One B-rep face of a CAD part: STEP entity #853.
In plain terms, the planar face has unit normal (0, 0, -1).
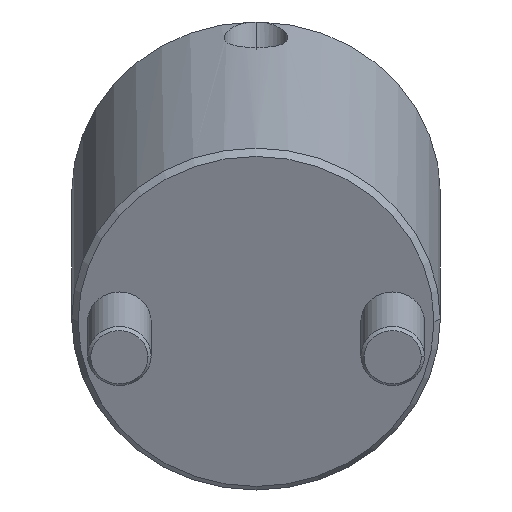
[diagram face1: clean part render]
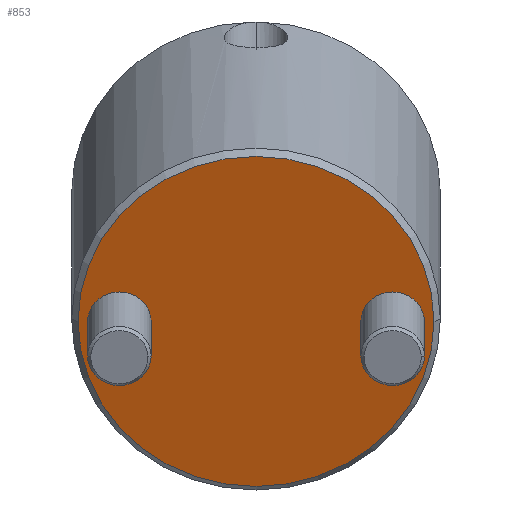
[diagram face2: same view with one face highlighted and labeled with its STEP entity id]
Its self-contained STEP definition (entity closure, numbers rounded to 3 decimals):
#432=CARTESIAN_POINT('',(0.,0.,
0.));
#433=DIRECTION('',(0.,0.,-1.));
#434=DIRECTION('',(0.,-1.,0.));
#435=AXIS2_PLACEMENT_3D('',#432,#433,#434);
#437=CARTESIAN_POINT('',(0.,0.,
0.));
#438=DIRECTION('',(0.,0.,-1.));
#439=DIRECTION('',(0.,1.,0.));
#440=AXIS2_PLACEMENT_3D('',#437,#438,#439);
#442=CARTESIAN_POINT('',(0.,-21.5,0.));
#443=DIRECTION('',(0.,0.,-1.));
#444=DIRECTION('',(0.,-1.,0.));
#445=AXIS2_PLACEMENT_3D('',#442,#443,#444);
#447=CARTESIAN_POINT('',(0.,-21.5,0.));
#448=DIRECTION('',(0.,0.,-1.));
#449=DIRECTION('',(0.,1.,0.));
#450=AXIS2_PLACEMENT_3D('',#447,#448,#449);
#452=CARTESIAN_POINT('',(0.,21.5,0.));
#453=DIRECTION('',(0.,0.,-1.));
#454=DIRECTION('',(0.,-1.,0.));
#455=AXIS2_PLACEMENT_3D('',#452,#453,#454);
#457=CARTESIAN_POINT('',(0.,21.5,0.));
#458=DIRECTION('',(0.,0.,-1.));
#459=DIRECTION('',(0.,1.,0.));
#460=AXIS2_PLACEMENT_3D('',#457,#458,#459);
#777=CARTESIAN_POINT('',(0.,-28.,0.));
#778=CARTESIAN_POINT('',(0.,28.,0.));
#779=VERTEX_POINT('',#777);
#780=VERTEX_POINT('',#778);
#806=CARTESIAN_POINT('',(0.,-26.5,0.));
#807=CARTESIAN_POINT('',(0.,-16.5,0.));
#808=VERTEX_POINT('',#806);
#809=VERTEX_POINT('',#807);
#810=CARTESIAN_POINT('',(0.,16.5,0.));
#811=CARTESIAN_POINT('',(0.,26.5,0.));
#812=VERTEX_POINT('',#810);
#813=VERTEX_POINT('',#811);
#830=CARTESIAN_POINT('',(0.,0.,0.));
#831=DIRECTION('',(0.,0.,1.));
#832=DIRECTION('',(0.,1.,0.));
#833=AXIS2_PLACEMENT_3D('',#830,#831,#832);
#834=PLANE('',#833);
#836=ORIENTED_EDGE('',*,*,#835,.F.);
#838=ORIENTED_EDGE('',*,*,#837,.F.);
#839=EDGE_LOOP('',(#836,#838));
#840=FACE_OUTER_BOUND('',#839,.F.);
#842=ORIENTED_EDGE('',*,*,#841,.T.);
#844=ORIENTED_EDGE('',*,*,#843,.T.);
#845=EDGE_LOOP('',(#842,#844));
#846=FACE_BOUND('',#845,.F.);
#848=ORIENTED_EDGE('',*,*,#847,.T.);
#850=ORIENTED_EDGE('',*,*,#849,.T.);
#851=EDGE_LOOP('',(#848,#850));
#852=FACE_BOUND('',#851,.F.);
#853=ADVANCED_FACE('',(#840,#846,#852),#834,.F.);
#436=CIRCLE('',#435,28.);
#441=CIRCLE('',#440,28.);
#446=CIRCLE('',#445,5.);
#451=CIRCLE('',#450,5.);
#456=CIRCLE('',#455,5.);
#461=CIRCLE('',#460,5.);
#835=EDGE_CURVE('',#779,#780,#436,.T.);
#837=EDGE_CURVE('',#780,#779,#441,.T.);
#841=EDGE_CURVE('',#808,#809,#446,.T.);
#843=EDGE_CURVE('',#809,#808,#451,.T.);
#847=EDGE_CURVE('',#812,#813,#456,.T.);
#849=EDGE_CURVE('',#813,#812,#461,.T.);
